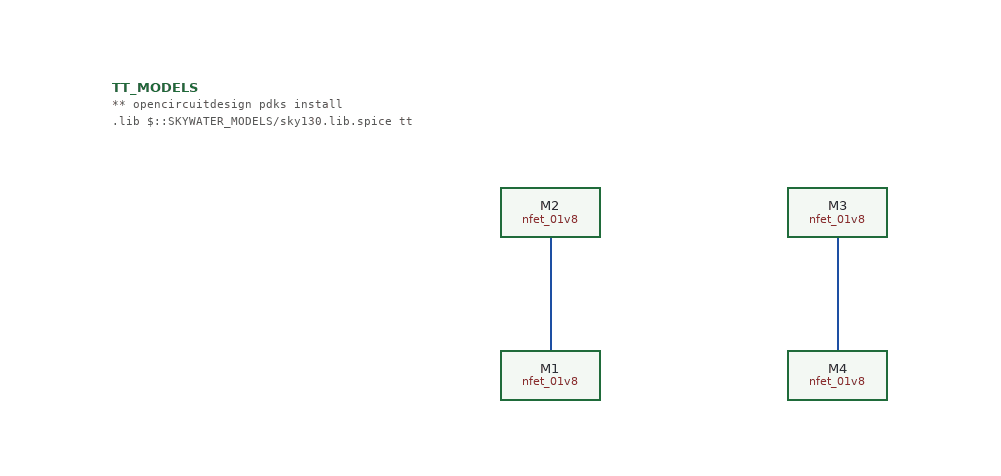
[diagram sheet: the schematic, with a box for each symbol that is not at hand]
v {xschem version=3.4.8RC file_version=1.3}
G {}
K {}
V {}
S {}
F {}
E {}
N -140 -40 -140 50 {lab=#net1}
N 90 -40 90 50 {lab=#net2}
C {sky130_fd_pr/nfet_01v8.sym} -120 -70 0 1 {name=M2
L=0.15
W=1  
nf=1 mult=1
model=nfet_01v8
spiceprefix=X
}
C {sky130_fd_pr/nfet_01v8.sym} -120 80 0 1 {name=M1
L=0.15
W=1  
nf=1 mult=1
model=nfet_01v8
spiceprefix=X
}
C {sky130_fd_pr/nfet_01v8.sym} 70 -70 0 0 {name=M3
L=0.15
W=1  
nf=1 mult=1
model=nfet_01v8
spiceprefix=X
}
C {sky130_fd_pr/nfet_01v8.sym} 70 80 0 0 {name=M4
L=0.15
W=1  
nf=1 mult=1
model=nfet_01v8
spiceprefix=X
}
C {devices/code.sym} -490 -160 0 0 {name=TT_MODELS
only_toplevel=true
format="tcleval( @value )"
value="
** opencircuitdesign pdks install
.lib $::SKYWATER_MODELS/sky130.lib.spice tt
"
spice_ignore=false}
